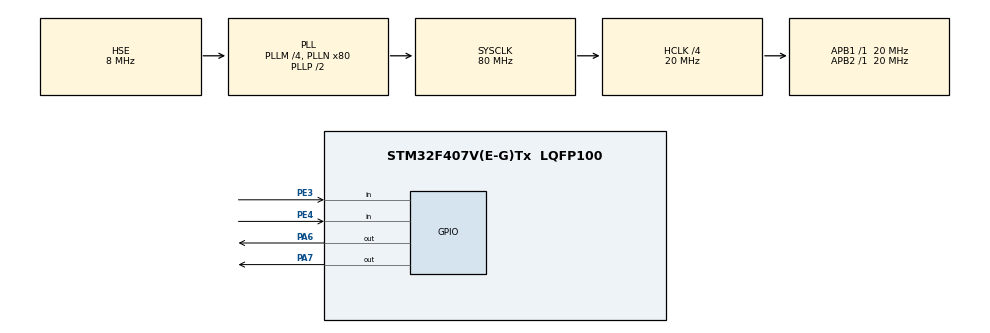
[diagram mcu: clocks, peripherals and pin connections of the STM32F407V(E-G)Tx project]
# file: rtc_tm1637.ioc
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Mcu.Family=STM32F4
Mcu.Name=STM32F407V(E-G)Tx
Mcu.Package=LQFP100
NVIC.PriorityGroup=NVIC_PRIORITYGROUP_4
PA13.Mode=Trace_Asynchronous_SW
PA13.Signal=SYS_JTMS-SWDIO
PA14.Mode=Trace_Asynchronous_SW
PA14.Signal=SYS_JTCK-SWCLK
PA6.GPIO_ModeDefaultOutputPP=GPIO_MODE_OUTPUT_OD
PA6.GPIO_PuPd=GPIO_PULLUP
PA6.Signal=GPIO_Output
PA7.GPIO_ModeDefaultOutputPP=GPIO_MODE_OUTPUT_OD
PA7.GPIO_PuPd=GPIO_PULLUP
PA7.Signal=GPIO_Output
PB3.Mode=Trace_Asynchronous_SW
PB3.Signal=SYS_JTDO-SWO
PC14-OSC32_IN.Mode=LSE-External-Oscillator
PC14-OSC32_IN.Signal=RCC_OSC32_IN
PC15-OSC32_OUT.Mode=LSE-External-Oscillator
PC15-OSC32_OUT.Signal=RCC_OSC32_OUT
PE3.GPIO_PuPd=GPIO_PULLUP
PE3.Signal=GPIO_Input
PE4.GPIO_PuPd=GPIO_PULLUP
PE4.Signal=GPIO_Input
PH0-OSC_IN.Mode=HSE-External-Oscillator
PH0-OSC_IN.Signal=RCC_OSC_IN
PH1-OSC_OUT.Mode=HSE-External-Oscillator
PH1-OSC_OUT.Signal=RCC_OSC_OUT
ProjectManager.HeapSize=0x200
ProjectManager.StackSize=0x400
ProjectManager.TargetToolchain=MDK-ARM V5.32
RCC.48MHZClocksFreq_Value=40000000
RCC.AHBCLKDivider=RCC_SYSCLK_DIV4
RCC.AHBFreq_Value=20000000
RCC.APB1Freq_Value=20000000
RCC.APB1TimFreq_Value=20000000
RCC.APB2Freq_Value=20000000
RCC.APB2TimFreq_Value=20000000
RCC.CortexFreq_Value=20000000
RCC.HCLKFreq_Value=20000000
RCC.HSE_VALUE=8000000
RCC.HSI_VALUE=16000000
RCC.PLLM=4
RCC.PLLN=80
RCC.PLLSourceVirtual=RCC_PLLSOURCE_HSE
RCC.RCC_RTC_Clock_Source=RCC_RTCCLKSOURCE_LSE
RCC.SYSCLKFreq_VALUE=80000000
RCC.SYSCLKSource=RCC_SYSCLKSOURCE_PLLCLK
RCC.VCOOutputFreq_Value=160000000
VP_RTC_VS_RTC_Activate.Mode=RTC_Enabled
board=custom

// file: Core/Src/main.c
/* USER CODE BEGIN Header */
/**
  ******************************************************************************
  * @file           : main.c
  * @brief          : Main program body
  ******************************************************************************
  * @attention
  *
  * <h2><center>&copy; Copyright (c) 2022 STMicroelectronics.
  * All rights reserved.</center></h2>
  *
  * This software component is licensed by ST under BSD 3-Clause license,
  * the "License"; You may not use this file except in compliance with the
  * License. You may obtain a copy of the License at:
  *                        opensource.org/licenses/BSD-3-Clause
  *
  ******************************************************************************
  */
/* USER CODE END Header */
#include "main.h"
#include "stm32_tm1637.h"
#include <stdio.h>
#define ITM_Port8(n)    (*((volatile unsigned char *)(0xE0000000+4*n)))
#define ITM_Port16(n)   (*((volatile unsigned short*)(0xE0000000+4*n)))
#define ITM_Port32(n)   (*((volatile unsigned long *)(0xE0000000+4*n)))
#define DEMCR           (*((volatile unsigned long *)(0xE000EDFC)))
#define TRCENA          0x01000000

struct __FILE { int handle; /* Add whatever you need here */ };
FILE __stdout;
FILE __stdin;

int fputc(int ch, FILE *f) {
   if (DEMCR & TRCENA) {

while (ITM_Port32(0) == 0){;};
    ITM_Port8(0) = ch;
  }
  return(ch);
}

RTC_HandleTypeDef hrtc;

void SystemClock_Config(void);
static void MX_GPIO_Init(void);
static void MX_RTC_Init(void);
/* USER CODE BEGIN PFP */
RTC_TimeTypeDef sTime = {0};
RTC_DateTypeDef sDate = {0};
char trans_str[64] = {0,};
/* USER CODE END PFP */

int _write(int32_t file, uint8_t *ptr, int32_t len)
{
/* Implement your write code here, this is used by puts and printf for example */
int i=0;
for(i=0 ; i<len ; i++)
ITM_SendChar((*ptr++));
return len;

}
int main(void)
{

  /* MCU Configuration--------------------------------------------------------*/

  /* Reset of all peripherals, Initializes the Flash interface and the Systick. */
  HAL_Init();

  /* Configure the system clock */
  SystemClock_Config();

  /* Initialize all configured peripherals */
  MX_GPIO_Init();
  MX_RTC_Init();
  tm1637Init();
  /* Infinite loop */
  /* USER CODE BEGIN WHILE */
	int fx = 0;

  while (1)
  {
    /* USER CODE END WHILE */
		HAL_RTC_GetTime(&hrtc, &sTime, RTC_FORMAT_BIN); // RTC_FORMAT_BIN , RTC_FORMAT_BCD
		HAL_RTC_GetDate(&hrtc, &sDate, FORMAT_BIN);

    fx = sTime.Hours*100;
		fx+=sTime.Minutes;
		tm1637DisplayDecimal(fx, sTime.Seconds%2==1 ? 1 : 0);
		HAL_Delay(10);
		if(!HAL_GPIO_ReadPin(GPIOE, GPIO_PIN_3)){
			if(sTime.Minutes == 59){
				sTime.Minutes = 0;
			} else sTime.Minutes +=1;
      sTime.Seconds = 0;
			HAL_RTC_SetTime(&hrtc, &sTime, RTC_FORMAT_BIN);
			HAL_Delay(100);
		}
		if(!HAL_GPIO_ReadPin(GPIOE, GPIO_PIN_4)){
      if(sTime.Hours==24){
				sTime.Hours = 0;
			} else sTime.Hours +=1;
      sTime.Seconds = 0;
			HAL_RTC_SetTime(&hrtc, &sTime, RTC_FORMAT_BIN);
			HAL_Delay(100);
		}
		printf("test");

  }
}

void SystemClock_Config(void)
{
  RCC_OscInitTypeDef RCC_OscInitStruct = {0};
  RCC_ClkInitTypeDef RCC_ClkInitStruct = {0};

  /** Configure the main internal regulator output voltage
  */
  __HAL_RCC_PWR_CLK_ENABLE();
  __HAL_PWR_VOLTAGESCALING_CONFIG(PWR_REGULATOR_VOLTAGE_SCALE1);
  /** Initializes the RCC Oscillators according to the specified parameters
  * in the RCC_OscInitTypeDef structure.
  */
  RCC_OscInitStruct.OscillatorType = RCC_OSCILLATORTYPE_HSE|RCC_OSCILLATORTYPE_LSE;
  RCC_OscInitStruct.HSEState = RCC_HSE_ON;
  RCC_OscInitStruct.LSEState = RCC_LSE_ON;
  RCC_OscInitStruct.PLL.PLLState = RCC_PLL_ON;
  RCC_OscInitStruct.PLL.PLLSource = RCC_PLLSOURCE_HSE;
  RCC_OscInitStruct.PLL.PLLM = 4;
  RCC_OscInitStruct.PLL.PLLN = 80;
  RCC_OscInitStruct.PLL.PLLP = RCC_PLLP_DIV2;
  RCC_OscInitStruct.PLL.PLLQ = 4;
  if (HAL_RCC_OscConfig(&RCC_OscInitStruct) != HAL_OK)
  {
    Error_Handler();
  }
  /** Initializes the CPU, AHB and APB buses clocks
  */
  RCC_ClkInitStruct.ClockType = RCC_CLOCKTYPE_HCLK|RCC_CLOCKTYPE_SYSCLK
                              |RCC_CLOCKTYPE_PCLK1|RCC_CLOCKTYPE_PCLK2;
  RCC_ClkInitStruct.SYSCLKSource = RCC_SYSCLKSOURCE_PLLCLK;
  RCC_ClkInitStruct.AHBCLKDivider = RCC_SYSCLK_DIV4;
  RCC_ClkInitStruct.APB1CLKDivider = RCC_HCLK_DIV1;
  RCC_ClkInitStruct.APB2CLKDivider = RCC_HCLK_DIV1;

  if (HAL_RCC_ClockConfig(&RCC_ClkInitStruct, FLASH_LATENCY_0) != HAL_OK)
  {
    Error_Handler();
  }
}

static void MX_RTC_Init(void)
{

	RTC_DateTypeDef DateToUpdate = {0};

  sTime.DayLightSaving = RTC_DAYLIGHTSAVING_NONE;
  sTime.StoreOperation = RTC_STOREOPERATION_RESET;

  /** Initialize RTC Only
  */
  hrtc.Instance = RTC;
  hrtc.Init.HourFormat = RTC_HOURFORMAT_24;
  hrtc.Init.AsynchPrediv = 127;
  hrtc.Init.SynchPrediv = 255;
  hrtc.Init.OutPut = RTC_OUTPUT_DISABLE;
  hrtc.Init.OutPutPolarity = RTC_OUTPUT_POLARITY_HIGH;
  hrtc.Init.OutPutType = RTC_OUTPUT_TYPE_OPENDRAIN;
  if (HAL_RTC_Init(&hrtc) != HAL_OK)
  {
    Error_Handler();
  }

  /* USER CODE BEGIN RTC_Init 2 */
  //if (HAL_RTC_SetTime(&hrtc, &sTime, RTC_FORMAT_BIN) != HAL_OK)
  //{
  //  Error_Handler();
  //}
  DateToUpdate.WeekDay = RTC_WEEKDAY_WEDNESDAY;
  DateToUpdate.Month = RTC_MONTH_MAY;
  DateToUpdate.Date = 18;
  DateToUpdate.Year = 22;
  /* USER CODE END RTC_Init 2 */

}

static void MX_GPIO_Init(void)
{
  GPIO_InitTypeDef GPIO_InitStruct = {0};

  /* GPIO Ports Clock Enable */
  __HAL_RCC_GPIOE_CLK_ENABLE();
  __HAL_RCC_GPIOC_CLK_ENABLE();
  __HAL_RCC_GPIOH_CLK_ENABLE();
  __HAL_RCC_GPIOA_CLK_ENABLE();
  __HAL_RCC_GPIOB_CLK_ENABLE();

  /*Configure GPIO pin Output Level */
  HAL_GPIO_WritePin(GPIOA, GPIO_PIN_6|GPIO_PIN_7, GPIO_PIN_RESET);
  HAL_GPIO_WritePin(GPIOA, GPIO_PIN_4|GPIO_PIN_5, GPIO_PIN_RESET);
  /*Configure GPIO pins : PE3 PE4 */
  GPIO_InitStruct.Pin = GPIO_PIN_3|GPIO_PIN_4;
  GPIO_InitStruct.Mode = GPIO_MODE_INPUT;
  GPIO_InitStruct.Pull = GPIO_PULLUP;
  HAL_GPIO_Init(GPIOE, &GPIO_InitStruct);

 GPIO_InitStruct.Pin = GPIO_PIN_4|GPIO_PIN_5;
  GPIO_InitStruct.Mode = GPIO_MODE_OUTPUT_OD;
  GPIO_InitStruct.Pull = GPIO_PULLUP;
  GPIO_InitStruct.Speed = GPIO_SPEED_FREQ_LOW;
  HAL_GPIO_Init(GPIOA, &GPIO_InitStruct);

  /*Configure GPIO pins : PA6 PA7 */
  GPIO_InitStruct.Pin = GPIO_PIN_6|GPIO_PIN_7;
  GPIO_InitStruct.Mode = GPIO_MODE_OUTPUT_OD;
  GPIO_InitStruct.Pull = GPIO_PULLUP;
  GPIO_InitStruct.Speed = GPIO_SPEED_FREQ_LOW;
  HAL_GPIO_Init(GPIOA, &GPIO_InitStruct);

}

void Error_Handler(void)
{
  __disable_irq();
  while (1)
  {
  }
}

/************************ (C) COPYRIGHT STMicroelectronics *****END OF FILE****/
